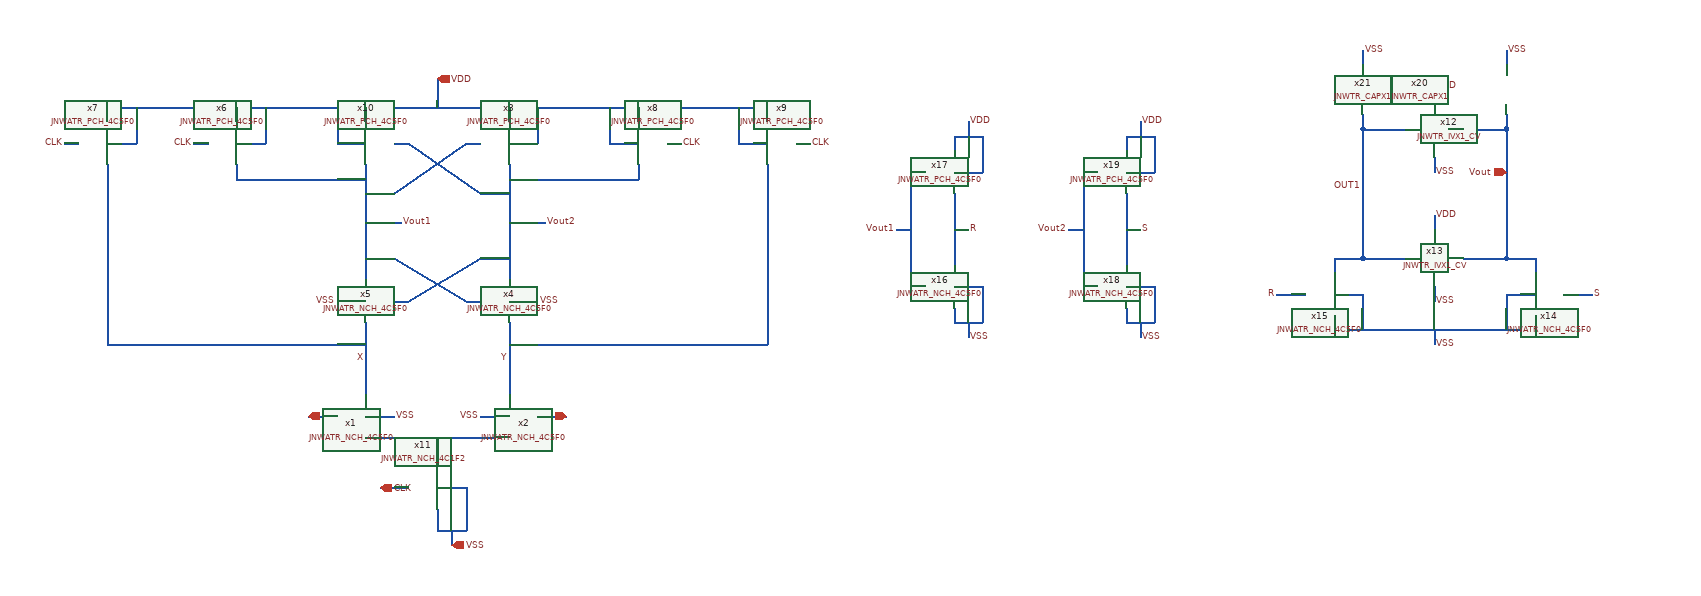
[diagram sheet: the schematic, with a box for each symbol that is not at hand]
v {xschem version=3.4.6 file_version=1.2}
G {}
K {}
V {}
S {}
E {}
N 1000 -550 1000 -450 {lab=Y}
N 800 -550 800 -450 {lab=X}
N 800 -770 800 -610 {lab=Vout1}
N 1000 -770 1000 -610 {lab=Vout2}
N 800 -390 1000 -390 {lab=#net1}
N 840 -580 860 -580 {lab=Vout2}
N 860 -580 960 -640 {lab=Vout2}
N 960 -640 1000 -640 {lab=Vout2}
N 940 -580 960 -580 {lab=Vout1}
N 840 -640 940 -580 {lab=Vout1}
N 800 -640 840 -640 {lab=Vout1}
N 840 -800 860 -800 {lab=Vout2}
N 940 -800 960 -800 {lab=Vout1}
N 620 -750 800 -750 {lab=Vout1}
N 1000 -750 1180 -750 {lab=Vout2}
N 1000 -520 1360 -520 {lab=Y}
N 1360 -770 1360 -520 {lab=Y}
N 440 -770 440 -520 {lab=X}
N 440 -520 800 -520 {lab=X}
N 440 -850 440 -830 {lab=VDD}
N 440 -850 1360 -850 {lab=VDD}
N 1360 -850 1360 -840 {lab=VDD}
N 1360 -840 1360 -830 {lab=VDD}
N 1180 -850 1180 -830 {lab=VDD}
N 1000 -850 1000 -830 {lab=VDD}
N 800 -850 800 -830 {lab=VDD}
N 620 -850 620 -830 {lab=VDD}
N 620 -800 660 -800 {lab=VDD}
N 660 -850 660 -800 {lab=VDD}
N 440 -800 480 -800 {lab=VDD}
N 480 -850 480 -800 {lab=VDD}
N 760 -800 800 -800 {lab=VDD}
N 760 -850 760 -800 {lab=VDD}
N 1000 -800 1040 -800 {lab=VDD}
N 1040 -850 1040 -800 {lab=VDD}
N 1140 -800 1180 -800 {lab=VDD}
N 1140 -850 1140 -800 {lab=VDD}
N 1320 -800 1360 -800 {lab=VDD}
N 1320 -850 1320 -800 {lab=VDD}
N 900 -390 900 -350 {lab=#net1}
N 900 -290 900 -260 {lab=VSS}
N 900 -320 940 -320 {lab=VSS}
N 940 -320 940 -260 {lab=VSS}
N 900 -260 940 -260 {lab=VSS}
N 920 -260 920 -240 {lab=VSS}
N 900 -890 900 -850 {lab=VDD}
N 800 -690 850 -690 {lab=Vout1}
N 1000 -690 1050 -690 {lab=Vout2}
N 720 -420 760 -420 {lab=Vin1}
N 1040 -420 1080 -420 {lab=Vin2}
N 560 -800 580 -800 {lab=CLK}
N 1220 -800 1240 -800 {lab=CLK}
N 1400 -800 1420 -800 {lab=CLK}
N 380 -800 400 -800 {lab=CLK}
N 980 -420 1000 -420 {lab=VSS}
N 1000 -580 1040 -580 {lab=VSS}
N 760 -580 800 -580 {lab=VSS}
N 960 -420 980 -420 {lab=VSS}
N 800 -420 840 -420 {lab=VSS}
N 800 -730 840 -730 {lab=Vout1}
N 840 -730 940 -800 {lab=Vout1}
N 960 -730 1000 -730 {lab=Vout2}
N 860 -800 960 -730 {lab=Vout2}
N 620 -770 620 -750 {lab=Vout1}
N 1180 -770 1180 -750 {lab=Vout2}
N 820 -320 860 -320 {lab=CLK}
N 1620 -570 1620 -550 {lab=VSS}
N 1620 -810 1620 -790 {lab=VDD}
N 1620 -730 1620 -630 {lab=R}
N 1620 -760 1660 -760 {lab=VDD}
N 1660 -810 1660 -760 {lab=VDD}
N 1620 -810 1660 -810 {lab=VDD}
N 1620 -600 1660 -600 {lab=VSS}
N 1660 -600 1660 -550 {lab=VSS}
N 1620 -550 1660 -550 {lab=VSS}
N 1640 -550 1640 -530 {lab=VSS}
N 1640 -830 1640 -810 {lab=VDD}
N 1560 -760 1580 -760 {lab=Vout1}
N 1560 -760 1560 -600 {lab=Vout1}
N 1560 -600 1580 -600 {lab=Vout1}
N 1540 -680 1560 -680 {lab=Vout1}
N 1620 -680 1640 -680 {lab=R}
N 1860 -570 1860 -550 {lab=VSS}
N 1860 -810 1860 -790 {lab=VDD}
N 1860 -730 1860 -630 {lab=S}
N 1860 -760 1900 -760 {lab=VDD}
N 1900 -810 1900 -760 {lab=VDD}
N 1860 -810 1900 -810 {lab=VDD}
N 1860 -600 1900 -600 {lab=VSS}
N 1900 -600 1900 -550 {lab=VSS}
N 1860 -550 1900 -550 {lab=VSS}
N 1880 -550 1880 -530 {lab=VSS}
N 1880 -830 1880 -810 {lab=VDD}
N 1800 -760 1820 -760 {lab=Vout2}
N 1800 -760 1800 -600 {lab=Vout2}
N 1800 -600 1820 -600 {lab=Vout2}
N 1780 -680 1800 -680 {lab=Vout2}
N 1860 -680 1880 -680 {lab=S}
N 2290 -780 2290 -760 {lab=VSS}
N 2290 -700 2290 -680 {lab=VDD}
N 2290 -600 2290 -580 {lab=VSS}
N 2290 -880 2290 -860 {lab=VDD}
N 2190 -640 2250 -640 {lab=OUT1}
N 2190 -820 2190 -640 {lab=OUT1}
N 2190 -820 2250 -820 {lab=OUT1}
N 2330 -820 2390 -820 {lab=Vout}
N 2390 -820 2390 -640 {lab=Vout}
N 2330 -640 2390 -640 {lab=Vout}
N 2390 -640 2430 -640 {lab=Vout}
N 2430 -640 2430 -620 {lab=Vout}
N 2150 -640 2190 -640 {lab=OUT1}
N 2150 -640 2150 -620 {lab=OUT1}
N 2070 -590 2110 -590 {lab=R}
N 2470 -590 2510 -590 {lab=S}
N 2430 -560 2430 -540 {lab=VSS}
N 2150 -540 2430 -540 {lab=VSS}
N 2150 -560 2150 -540 {lab=VSS}
N 2150 -590 2190 -590 {lab=VSS}
N 2190 -590 2190 -540 {lab=VSS}
N 2390 -590 2430 -590 {lab=VSS}
N 2390 -590 2390 -540 {lab=VSS}
N 2290 -540 2290 -520 {lab=VSS}
N 2390 -840 2390 -820 {lab=Vout}
N 2190 -840 2190 -820 {lab=OUT1}
N 2390 -930 2390 -910 {lab=VSS}
N 2190 -930 2190 -910 {lab=VSS}
C {devices/ipin.sym} 900 -890 2 1 {name=p1 lab=VDD
}
C {devices/ipin.sym} 920 -240 2 1 {name=p2 lab=VSS

}
C {devices/ipin.sym} 720 -420 2 1 {name=p4 lab=Vin1

}
C {devices/ipin.sym} 1080 -420 2 0 {name=p5 lab=Vin2

}
C {devices/ipin.sym} 820 -320 2 1 {name=p6 lab=CLK

}
C {JNW_ATR_SKY130A/JNWATR_NCH_4C5F0.sym} 760 -420 0 0 {name=x1 }
C {JNW_ATR_SKY130A/JNWATR_NCH_4C5F0.sym} 1040 -420 0 1 {name=x2 }
C {JNW_ATR_SKY130A/JNWATR_PCH_4C5F0.sym} 960 -800 0 0 {name=x3 }
C {JNW_ATR_SKY130A/JNWATR_NCH_4C5F0.sym} 960 -580 0 0 {name=x4 }
C {JNW_ATR_SKY130A/JNWATR_NCH_4C5F0.sym} 840 -580 0 1 {name=x5 }
C {JNW_ATR_SKY130A/JNWATR_PCH_4C5F0.sym} 580 -800 0 0 {name=x6 }
C {JNW_ATR_SKY130A/JNWATR_PCH_4C5F0.sym} 400 -800 0 0 {name=x7 }
C {JNW_ATR_SKY130A/JNWATR_PCH_4C5F0.sym} 1220 -800 0 1 {name=x8 }
C {JNW_ATR_SKY130A/JNWATR_PCH_4C5F0.sym} 1400 -800 0 1 {name=x9 }
C {JNW_ATR_SKY130A/JNWATR_PCH_4C5F0.sym} 840 -800 0 1 {name=x10 }
C {JNW_ATR_SKY130A/JNWATR_NCH_4C1F2.sym} 860 -320 0 0 {name=x11 }
C {devices/opin.sym} 2390 -760 2 1 {name=p7 lab=Vout
}
C {devices/lab_pin.sym} 800 -500 0 0 {name=p8 sig_type=std_logic lab=X}
C {devices/lab_pin.sym} 1000 -500 0 0 {name=p9 sig_type=std_logic lab=Y}
C {devices/lab_pin.sym} 760 -580 0 0 {name=p10 sig_type=std_logic lab=VSS}
C {devices/lab_pin.sym} 1040 -580 0 1 {name=p11 sig_type=std_logic lab=VSS}
C {devices/lab_pin.sym} 960 -420 0 0 {name=p12 sig_type=std_logic lab=VSS}
C {devices/lab_pin.sym} 840 -420 0 1 {name=p13 sig_type=std_logic lab=VSS}
C {devices/lab_pin.sym} 380 -800 0 0 {name=p14 sig_type=std_logic lab=CLK}
C {devices/lab_pin.sym} 560 -800 0 0 {name=p15 sig_type=std_logic lab=CLK}
C {devices/lab_pin.sym} 1240 -800 0 1 {name=p16 sig_type=std_logic lab=CLK}
C {devices/lab_pin.sym} 1420 -800 0 1 {name=p17 sig_type=std_logic lab=CLK}
C {JNW_ATR_SKY130A/JNWATR_NCH_4C5F0.sym} 1580 -600 0 0 {name=x16 }
C {JNW_ATR_SKY130A/JNWATR_PCH_4C5F0.sym} 1580 -760 0 0 {name=x17 }
C {devices/lab_pin.sym} 1640 -530 0 1 {name=p27 sig_type=std_logic lab=VSS}
C {devices/lab_pin.sym} 1640 -830 0 1 {name=p28 sig_type=std_logic lab=VDD}
C {devices/lab_pin.sym} 1540 -680 0 0 {name=p29 sig_type=std_logic lab=Vout1}
C {devices/lab_pin.sym} 1640 -680 0 1 {name=p30 sig_type=std_logic lab=R}
C {JNW_ATR_SKY130A/JNWATR_NCH_4C5F0.sym} 1820 -600 0 0 {name=x18 }
C {JNW_ATR_SKY130A/JNWATR_PCH_4C5F0.sym} 1820 -760 0 0 {name=x19 }
C {devices/lab_pin.sym} 1880 -530 0 1 {name=p31 sig_type=std_logic lab=VSS}
C {devices/lab_pin.sym} 1880 -830 0 1 {name=p32 sig_type=std_logic lab=VDD}
C {devices/lab_pin.sym} 1780 -680 0 0 {name=p33 sig_type=std_logic lab=Vout2}
C {devices/lab_pin.sym} 1880 -680 0 1 {name=p34 sig_type=std_logic lab=S}
C {JNW_TR_SKY130A/JNWTR_IVX1_CV.sym} 2250 -820 0 0 {name=x12 }
C {JNW_TR_SKY130A/JNWTR_IVX1_CV.sym} 2330 -640 0 1 {name=x13 }
C {devices/lab_pin.sym} 2290 -580 0 1 {name=p18 sig_type=std_logic lab=VSS}
C {devices/lab_pin.sym} 2290 -760 0 1 {name=p19 sig_type=std_logic lab=VSS}
C {devices/lab_pin.sym} 2290 -700 0 1 {name=p20 sig_type=std_logic lab=VDD}
C {devices/lab_pin.sym} 2290 -880 0 1 {name=p21 sig_type=std_logic lab=VDD}
C {JNW_ATR_SKY130A/JNWATR_NCH_4C5F0.sym} 2470 -590 0 1 {name=x14 }
C {JNW_ATR_SKY130A/JNWATR_NCH_4C5F0.sym} 2110 -590 0 0 {name=x15 }
C {devices/lab_pin.sym} 2290 -520 0 1 {name=p22 sig_type=std_logic lab=VSS}
C {devices/lab_pin.sym} 2510 -590 0 1 {name=p23 sig_type=std_logic lab=S}
C {devices/lab_pin.sym} 2070 -590 0 0 {name=p24 sig_type=std_logic lab=R}
C {devices/lab_pin.sym} 2190 -740 0 0 {name=p26 sig_type=std_logic lab=OUT1}
C {JNW_TR_SKY130A/JNWTR_CAPX1.sym} 2390 -850 0 0 {name=x20 }
C {JNW_TR_SKY130A/JNWTR_CAPX1.sym} 2190 -850 0 1 {name=x21 }
C {devices/lab_pin.sym} 2190 -930 0 1 {name=p35 sig_type=std_logic lab=VSS}
C {devices/lab_pin.sym} 2390 -930 0 1 {name=p36 sig_type=std_logic lab=VSS}
C {devices/lab_pin.sym} 850 -690 0 1 {name=p3 sig_type=std_logic lab=Vout1}
C {devices/lab_pin.sym} 1050 -690 0 1 {name=p25 sig_type=std_logic lab=Vout2}
